VERSION 5.7 ;
BUSBITCHARS "[]" ;
DIVIDERCHAR "/" ;

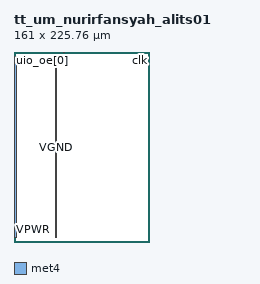
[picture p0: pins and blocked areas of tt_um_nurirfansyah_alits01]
MACRO tt_um_nurirfansyah_alits01
  CLASS BLOCK ;
  ORIGIN 0 0 ;
  SIZE 161 BY 225.76 ;

  SYMMETRY X Y ;
  SITE unithd ;

  # --------------------
  # STANDARD INPUT PINS
  # --------------------
  PIN clk
    DIRECTION INPUT ;
    USE SIGNAL ;
    PORT
      LAYER met4 ;
      RECT 154.87 224.76 155.17 225.76 ;
    END
  END clk

  PIN ena
    DIRECTION INPUT ;
    USE SIGNAL ;
    PORT
      LAYER met4 ;
      RECT 158.55 224.76 158.85 225.76 ;
    END
  END ena

  PIN rst_n
    DIRECTION INPUT ;
    USE SIGNAL ;
    PORT
      LAYER met4 ;
      RECT 151.19 224.76 151.49 225.76 ;
    END
  END rst_n

  # --------------------
  # UI INPUTS
  # --------------------
  PIN ui_in[0]
    DIRECTION INPUT ;
    USE SIGNAL ;
    PORT
      LAYER met4 ;
      RECT 147.51 224.76 147.81 225.76 ;
    END
  END ui_in[0]

  # Repeat ui_in[1..7] EXACTLY same as DEF

  # --------------------
  # UO OUTPUTS
  # --------------------
  PIN uo_out[0]
    DIRECTION OUTPUT ;
    USE SIGNAL ;
    PORT
      LAYER met4 ;
      RECT 88.63 224.76 88.93 225.76 ;
    END
  END uo_out[0]

  # Repeat uo_out[1..7]

  # --------------------
  # UIO (REQUIRED)
  # --------------------
  PIN uio_in[0]
    DIRECTION INPUT ;
    USE SIGNAL ;
    PORT
      LAYER met4 ;
      RECT 118.07 224.76 118.37 225.76 ;
    END
  END uio_in[0]

  PIN uio_out[0]
    DIRECTION OUTPUT ;
    USE SIGNAL ;
    PORT
      LAYER met4 ;
      RECT 59.19 224.76 59.49 225.76 ;
    END
  END uio_out[0]

  PIN uio_oe[0]
    DIRECTION OUTPUT ;
    USE SIGNAL ;
    PORT
      LAYER met4 ;
      RECT 29.75 224.76 30.05 225.76 ;
    END
  END uio_oe[0]

  # Repeat for [1..7]

  # --------------------
  # POWER
  # --------------------
  PIN VPWR
    DIRECTION INOUT ;
    USE POWER ;
    PORT
      LAYER met4 ;
      RECT 1.0 5.0 2.5 220.76 ;
    END
  END VPWR

  PIN VGND
    DIRECTION INOUT ;
    USE GROUND ;
    PORT
      LAYER met4 ;
      RECT 49.0 5.0 50.5 220.76 ;
    END
  END VGND

END tt_um_nurirfansyah_alits01
END LIBRARY
